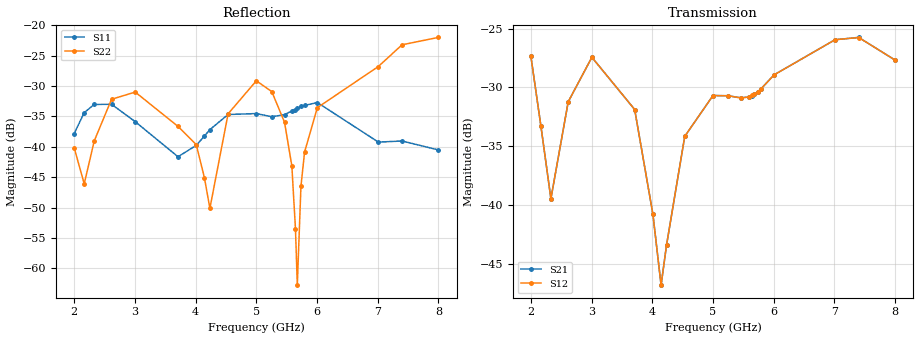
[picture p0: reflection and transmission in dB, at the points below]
!Agilent Technologies,E8364B,MY43040699,A.07.50.67
!Agilent E8364B: A.07.50.67
!Date: Friday, June 06, 2025 05:55:27
!Correction: S11(Full 2 Port(1,2))
!S21(Full 2 Port(1,2))
!S12(Full 2 Port(1,2))
!S22(Full 2 Port(1,2))
!S2P File: Measurements: S11, S21, S12, S22:
# Hz S  dB  R 50
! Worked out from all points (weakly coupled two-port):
!   401 points, 2 GHz to 8 GHz, reference 50 ohm
!   highest |S21| = -25.74 dB at 7.4 GHz (marker M1); lowest = -46.8 dB at 4.145 GHz (marker M2)
!   lowest |S11| = -41.7 dB at 3.71 GHz (marker M3), VSWR 1.02, Z = 49.8 + j0.787 ohm
!   |S11| at or under -10 dB: start of sweep to end of sweep
!   |S22| runs from -62.8 to -21.8 dB; largest |S21 - S12| = 0.00018
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2e9  -37.83 -14.0  -27.35 30.5  -27.34 30.5  -40.19 -47.6
2.165e9  -34.39 -33.9  -33.28 19.4  -33.27 19.3  -46.11 -137.6
2.33e9  -33.05 -55.9  -39.48 56.2  -39.47 56.1  -39.05 134.0
2.615e9  -33.02 -95.4  -31.23 75.7  -31.22 75.6  -32.20 76.7
3.005e9  -35.88 -155.6  -27.44 21.7  -27.43 21.6  -31.01 25.5
3.71e9  -41.65 107.0  -31.88 -95.9  -31.88 -95.9  -36.66 6.2
4.01e9  -39.78 96.2  -40.78 -164.4  -40.80 -164.4  -39.65 -5.5
4.145e9  -38.25 87.6  -46.83 114.1  -46.83 114.3  -45.10 -3.6
4.235e9  -37.19 79.2  -43.42 51.8  -43.40 51.8  -50.13 38.7
4.535e9  -34.70 43.5  -34.17 -24.2  -34.16 -24.0  -34.59 88.4
5e9  -34.55 -33.6  -30.69 -95.1  -30.69 -95.1  -29.16 31.9
5.255e9  -35.07 -87.7  -30.71 -125.0  -30.71 -124.8  -30.94 -1.0
5.465e9  -34.73 -135.8  -30.89 -143.4  -30.91 -143.5  -35.99 -27.8
5.585e9  -34.11 -160.6  -30.81 -152.2  -30.81 -152.2  -43.14 -40.3
5.645e9  -33.91 -172.7  -30.69 -156.4  -30.68 -156.4  -53.58 -36.1
5.675e9  -33.70 -178.7  -30.59 -158.5  -30.60 -158.5  -62.76 56.8
5.735e9  -33.34 170.9  -30.38 -162.7  -30.38 -162.8  -46.49 108.7
5.795e9  -33.22 160.4  -30.10 -167.2  -30.10 -167.1  -40.86 104.9
6.005e9  -32.73 130.2  -28.93 175.2  -28.94 175.2  -33.58 83.8
7.01e9  -39.24 88.3  -25.94 65.1  -25.94 64.9  -26.81 60.2
7.4e9  -39.06 92.2  -25.74 23.0  -25.75 23.0  -23.24 33.7
8e9  -40.53 73.2  -27.68 -43.3  -27.67 -43.4  -22.02 -20.8
